VERSION 5.7 ;
  NOWIREEXTENSIONATPIN ON ;
  DIVIDERCHAR "/" ;
  BUSBITCHARS "[]" ;
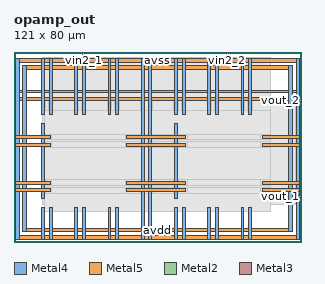
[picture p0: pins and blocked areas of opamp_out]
MACRO opamp_out
  CLASS BLOCK ;
  FOREIGN opamp_out ;
  ORIGIN 0.000 0.000 ;
  SIZE 121.000 BY 80.000 ;
  PIN avdd
    DIRECTION INOUT ;
    USE POWER ;
    PORT
      LAYER Metal4 ;
        RECT 3.700 4.260 5.200 74.140 ;
    END
    PORT
      LAYER Metal4 ;
        RECT 115.760 4.260 117.260 74.140 ;
    END
    PORT
      LAYER Metal5 ;
        RECT 3.700 4.260 117.260 5.760 ;
    END
    PORT
      LAYER Metal5 ;
        RECT 3.700 72.640 117.260 74.140 ;
    END
    PORT
      LAYER Metal4 ;
        RECT 11.600 1.260 12.800 14.720 ;
    END
    PORT
      LAYER Metal4 ;
        RECT 11.600 18.280 12.800 49.920 ;
    END
    PORT
      LAYER Metal4 ;
        RECT 11.600 53.480 12.800 77.140 ;
    END
    PORT
      LAYER Metal4 ;
        RECT 25.600 1.260 26.800 14.720 ;
    END
    PORT
      LAYER Metal4 ;
        RECT 25.600 53.480 26.800 77.140 ;
    END
    PORT
      LAYER Metal4 ;
        RECT 39.600 1.260 40.800 14.720 ;
    END
    PORT
      LAYER Metal4 ;
        RECT 39.600 53.480 40.800 77.140 ;
    END
    PORT
      LAYER Metal4 ;
        RECT 53.600 1.260 54.800 77.140 ;
    END
    PORT
      LAYER Metal4 ;
        RECT 67.600 1.260 68.800 14.720 ;
    END
    PORT
      LAYER Metal4 ;
        RECT 67.600 18.280 68.800 49.920 ;
    END
    PORT
      LAYER Metal4 ;
        RECT 67.600 53.480 68.800 77.140 ;
    END
    PORT
      LAYER Metal4 ;
        RECT 81.600 1.260 82.800 14.720 ;
    END
    PORT
      LAYER Metal4 ;
        RECT 81.600 53.480 82.800 77.140 ;
    END
    PORT
      LAYER Metal4 ;
        RECT 95.600 1.260 96.800 14.720 ;
    END
    PORT
      LAYER Metal4 ;
        RECT 95.600 53.480 96.800 77.140 ;
    END
    PORT
      LAYER Metal5 ;
        RECT 0.700 21.160 15.330 22.360 ;
    END
    PORT
      LAYER Metal5 ;
        RECT 0.700 40.360 15.330 41.560 ;
    END
    PORT
      LAYER Metal5 ;
        RECT 0.700 59.560 120.260 60.760 ;
    END
    PORT
      LAYER Metal5 ;
        RECT 47.450 21.160 72.330 22.360 ;
    END
    PORT
      LAYER Metal5 ;
        RECT 47.450 40.360 72.330 41.560 ;
    END
    PORT
      LAYER Metal5 ;
        RECT 104.450 21.160 120.260 22.360 ;
    END
    PORT
      LAYER Metal5 ;
        RECT 104.450 40.360 120.260 41.560 ;
    END
  END avdd
  PIN avss
    DIRECTION INOUT ;
    USE GROUND ;
    PORT
      LAYER Metal4 ;
        RECT 0.700 1.260 2.200 77.140 ;
    END
    PORT
      LAYER Metal4 ;
        RECT 118.760 1.260 120.260 77.140 ;
    END
    PORT
      LAYER Metal5 ;
        RECT 0.700 1.260 120.260 2.760 ;
    END
    PORT
      LAYER Metal5 ;
        RECT 0.700 75.640 120.260 77.140 ;
    END
    PORT
      LAYER Metal4 ;
        RECT 14.800 1.260 16.000 14.720 ;
    END
    PORT
      LAYER Metal4 ;
        RECT 14.800 53.480 16.000 77.140 ;
    END
    PORT
      LAYER Metal4 ;
        RECT 28.800 1.260 30.000 14.720 ;
    END
    PORT
      LAYER Metal4 ;
        RECT 28.800 53.480 30.000 77.140 ;
    END
    PORT
      LAYER Metal4 ;
        RECT 42.800 1.260 44.000 14.720 ;
    END
    PORT
      LAYER Metal4 ;
        RECT 42.800 53.480 44.000 77.140 ;
    END
    PORT
      LAYER Metal4 ;
        RECT 56.800 1.260 58.000 77.140 ;
    END
    PORT
      LAYER Metal4 ;
        RECT 70.800 1.260 72.000 14.720 ;
    END
    PORT
      LAYER Metal4 ;
        RECT 70.800 53.480 72.000 77.140 ;
    END
    PORT
      LAYER Metal4 ;
        RECT 84.800 1.260 86.000 14.720 ;
    END
    PORT
      LAYER Metal4 ;
        RECT 84.800 53.480 86.000 77.140 ;
    END
    PORT
      LAYER Metal4 ;
        RECT 98.800 1.260 100.000 14.720 ;
    END
    PORT
      LAYER Metal4 ;
        RECT 98.800 53.480 100.000 77.140 ;
    END
    PORT
      LAYER Metal5 ;
        RECT 0.700 24.360 15.330 25.560 ;
    END
    PORT
      LAYER Metal5 ;
        RECT 0.700 43.560 15.330 44.760 ;
    END
    PORT
      LAYER Metal5 ;
        RECT 0.700 62.760 120.260 63.960 ;
    END
    PORT
      LAYER Metal5 ;
        RECT 47.450 24.360 72.330 25.560 ;
    END
    PORT
      LAYER Metal5 ;
        RECT 47.450 43.560 72.330 44.760 ;
    END
    PORT
      LAYER Metal5 ;
        RECT 104.450 24.360 120.260 25.560 ;
    END
    PORT
      LAYER Metal5 ;
        RECT 104.450 43.560 120.260 44.760 ;
    END
  END avss
  PIN vin2_1
    DIRECTION INPUT ;
    USE SIGNAL ;
    ANTENNAGATEAREA 5.000000 ;
    PORT
      LAYER Metal2 ;
        RECT 28.980 77.500 29.820 80.000 ;
    END
  END vin2_1
  PIN vin2_2
    DIRECTION INPUT ;
    USE SIGNAL ;
    ANTENNAGATEAREA 5.000000 ;
    PORT
      LAYER Metal2 ;
        RECT 89.460 77.500 90.300 80.000 ;
    END
  END vin2_2
  PIN vout_1
    DIRECTION OUTPUT ;
    USE SIGNAL ;
    ANTENNAGATEAREA 5.000000 ;
    ANTENNADIFFAREA 10.568000 ;
    PORT
      LAYER Metal3 ;
        RECT 118.500 18.900 121.000 19.740 ;
    END
  END vout_1
  PIN vout_2
    DIRECTION OUTPUT ;
    USE SIGNAL ;
    ANTENNAGATEAREA 5.000000 ;
    ANTENNADIFFAREA 10.568000 ;
    PORT
      LAYER Metal3 ;
        RECT 118.500 59.220 121.000 60.060 ;
    END
  END vout_2
  OBS
      LAYER Nwell ;
        RECT 22.090 21.680 97.810 44.040 ;
      LAYER Metal1 ;
        RECT 13.000 16.000 106.815 52.200 ;
      LAYER Metal2 ;
        RECT 11.900 77.200 28.680 77.500 ;
        RECT 30.120 77.200 89.160 77.500 ;
        RECT 90.600 77.200 108.105 77.500 ;
        RECT 11.900 16.000 108.105 77.200 ;
      LAYER Metal3 ;
        RECT 11.850 58.920 118.200 60.340 ;
        RECT 11.850 20.040 118.500 58.920 ;
        RECT 11.850 18.600 118.200 20.040 ;
        RECT 11.850 16.000 118.500 18.600 ;
      LAYER Metal4 ;
        RECT 13.100 53.180 14.500 59.830 ;
        RECT 16.300 53.180 25.300 59.830 ;
        RECT 27.100 53.180 28.500 59.830 ;
        RECT 30.300 53.180 39.300 59.830 ;
        RECT 41.100 53.180 42.500 59.830 ;
        RECT 44.300 53.180 53.300 59.830 ;
        RECT 13.000 50.220 53.300 53.180 ;
        RECT 13.100 17.980 53.300 50.220 ;
        RECT 13.000 16.000 53.300 17.980 ;
        RECT 55.100 16.000 56.500 59.830 ;
        RECT 58.300 53.180 67.300 59.830 ;
        RECT 69.100 53.180 70.500 59.830 ;
        RECT 72.300 53.180 81.300 59.830 ;
        RECT 83.100 53.180 84.500 59.830 ;
        RECT 86.300 53.180 95.300 59.830 ;
        RECT 97.100 53.180 98.500 59.830 ;
        RECT 100.300 53.180 108.105 59.830 ;
        RECT 58.300 50.220 108.105 53.180 ;
        RECT 58.300 17.980 67.300 50.220 ;
        RECT 69.100 17.980 108.105 50.220 ;
        RECT 58.300 16.000 108.105 17.980 ;
      LAYER Metal5 ;
        RECT 13.000 45.360 108.105 55.200 ;
        RECT 15.930 42.960 46.850 45.360 ;
        RECT 72.930 42.960 103.850 45.360 ;
        RECT 13.000 42.160 108.105 42.960 ;
        RECT 15.930 39.760 46.850 42.160 ;
        RECT 72.930 39.760 103.850 42.160 ;
        RECT 13.000 26.160 108.105 39.760 ;
        RECT 15.930 23.760 46.850 26.160 ;
        RECT 72.930 23.760 103.850 26.160 ;
        RECT 13.000 22.960 108.105 23.760 ;
        RECT 15.930 20.560 46.850 22.960 ;
        RECT 72.930 20.560 103.850 22.960 ;
        RECT 13.000 13.000 108.105 20.560 ;
  END
END opamp_out
END LIBRARY

